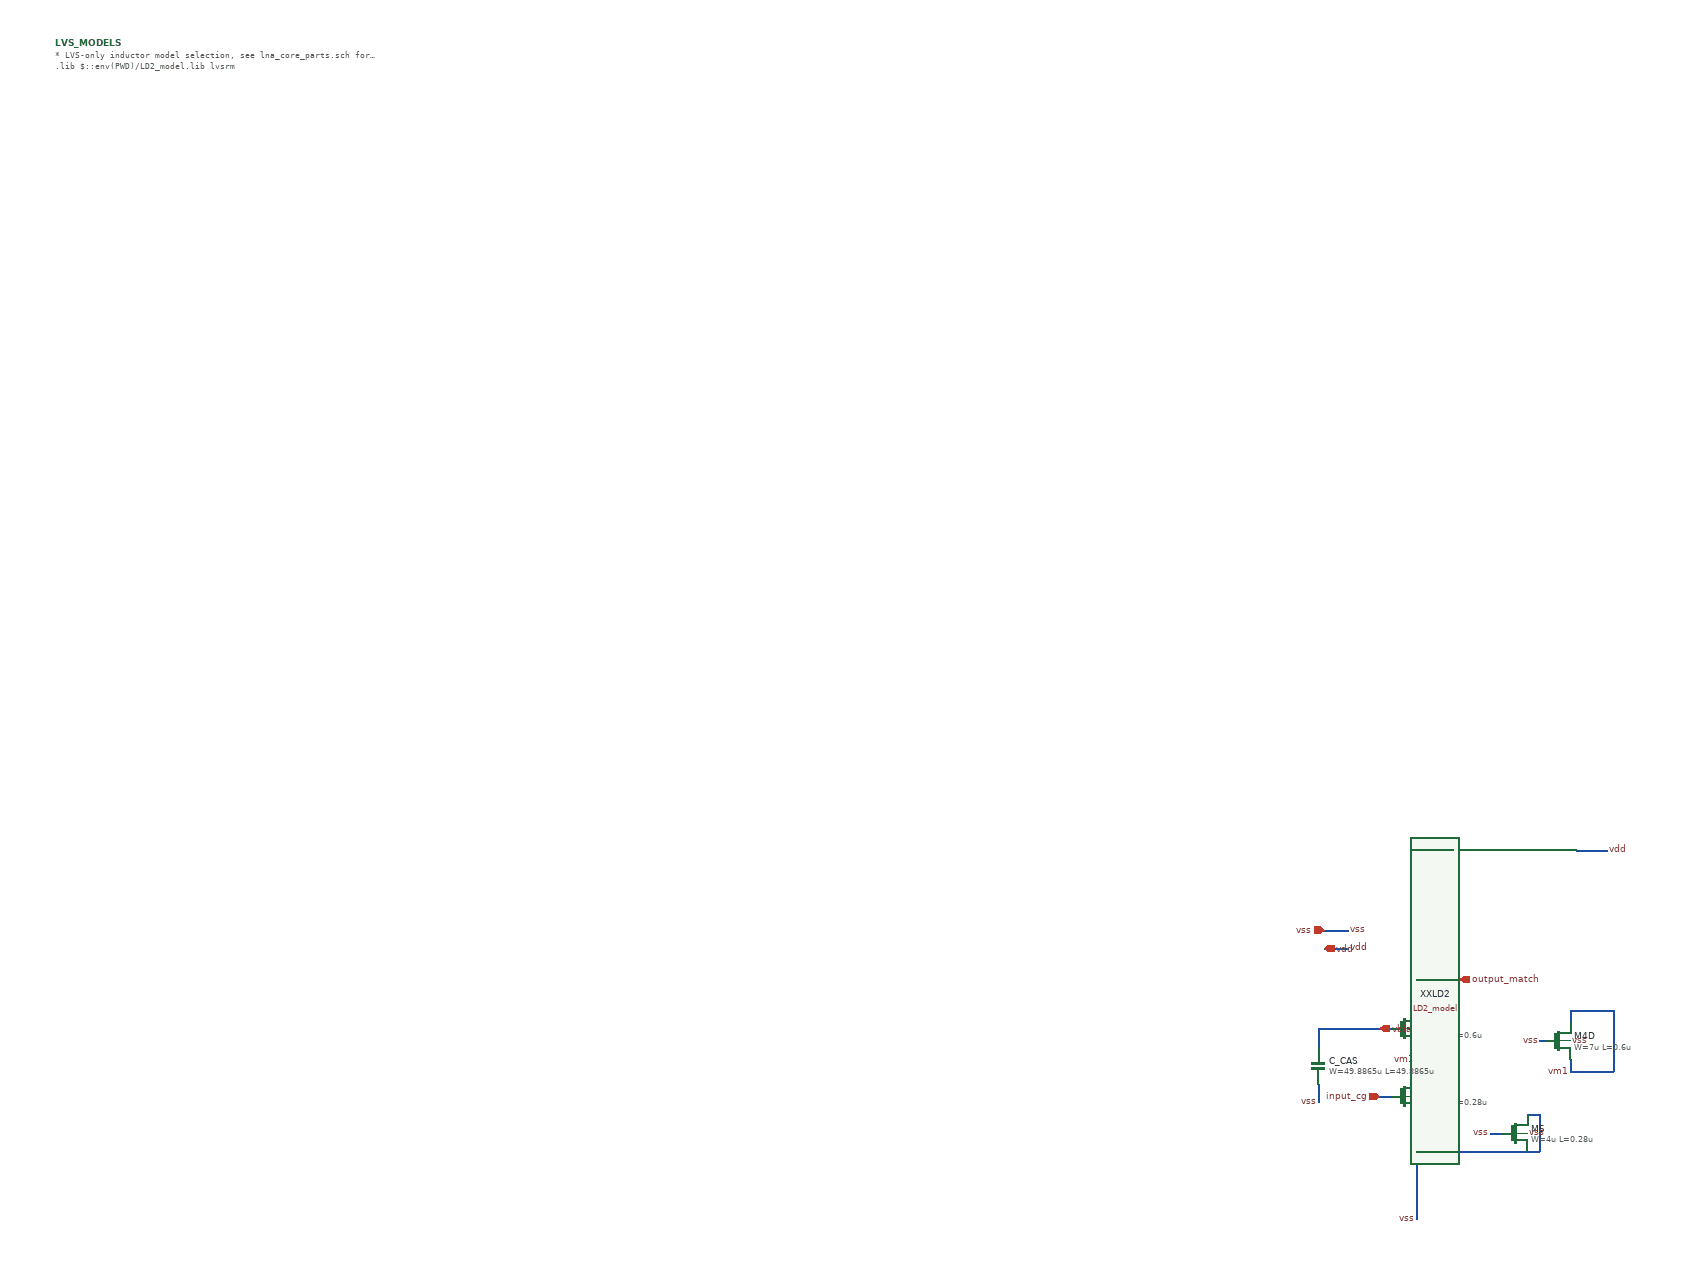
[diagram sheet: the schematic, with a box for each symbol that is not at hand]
v {xschem version=3.4.8RC file_version=1.3}
G {}
K {}
V {}
S {}
F {}
E {}
N 460 -430 460 -410 {lab=vm1}
N 460 -350 460 -330 {lab=vm1}
N 410 -380 420 -380 {lab=vss}
N 210 -290 230 -290 {
lab=vss}
N 210 -260 210 -250 {
lab=vss}
N 150 -290 170 -290 {
lab=input_cg}
N 210 -250 210 -190 {
lab=vss}
N 210 -400 230 -400 {
lab=vss}
N 210 -370 210 -360 {
lab=vm1}
N 150 -400 170 -400 {
lab=vbias_cas}
N 210 -360 210 -320 {
lab=vm1}
N 210 -190 210 -180 {
lab=vss}
N 210 -120 210 -110 {
lab=vss}
N 210 -110 210 -90 {
lab=vss}
N 210 -480 280 -480 {
lab=output_match}
N 210 -490 210 -430 {lab=output_match}
N 210 -200 390 -200 {lab=vss}
N 390 -260 410 -260 {lab=vss}
N 410 -260 410 -200 {lab=vss}
N 390 -200 410 -200 {lab=vss}
N 330 -230 350 -230 {lab=vss}
N 460 -330 530 -330 {lab=vm1}
N 530 -430 530 -330 {lab=vm1}
N 460 -430 530 -430 {lab=vm1}
N 60 -560 100 -560 {lab=vss}
N 210 -690 270 -690 {lab=output_match}
N 60 -530 100 -530 {lab=vdd}
N 210 -690 210 -490 {lab=output_match}
N 470 -690 520 -690 {lab=vdd}
N 50 -400 150 -400 {lab=vbias_cas}
N 50 -400 50 -370 {lab=vbias_cas}
N 50 -310 50 -280 {lab=vss}
N 210 -180 210 -120 {lab=vss}
C {ipin.sym} 150 -290 0 0 {name=p1 lab=input_cg}
C {opin.sym} 280 -480 0 0 {name=p2 lab=output_match}
C {iopin.sym} 60 -530 0 1 {name=p3 lab=vdd}
C {symbols/nfet_05v0.sym} 440 -380 0 0 {name=M4D
L=0.6u
W=7u
nf=2
m=2
ad="'int((nf+1)/2) * W/nf * 0.18u'"
pd="'2*int((nf+1)/2) * (W/nf + 0.18u)'"
as="'int((nf+2)/2) * W/nf * 0.18u'"
ps="'2*int((nf+2)/2) * (W/nf + 0.18u)'"
nrd="'0.18u / W'" nrs="'0.18u / W'"
sa=0 sb=0 sd=0
model=nfet_05v0
spiceprefix=X
}
C {lab_pin.sym} 410 -380 0 0 {name=pM4D_g sig_type=std_logic lab=vss}
C {lab_pin.sym} 460 -380 2 0 {name=pM4D_b sig_type=std_logic lab=vss}
C {symbols/nfet_05v0.sym} 190 -400 0 0 {name=M2
L=0.6u
W=35u
nf=10
m=4
ad="'int((nf+1)/2) * W/nf * 0.18u'"
pd="'2*int((nf+1)/2) * (W/nf + 0.18u)'"
as="'int((nf+2)/2) * W/nf * 0.18u'"
ps="'2*int((nf+2)/2) * (W/nf + 0.18u)'"
nrd="'0.18u / W'" nrs="'0.18u / W'"
sa=0 sb=0 sd=0
model=nfet_05v0
spiceprefix=X
}
C {symbols/nfet_03v3.sym} 190 -290 0 0 {name=M3
L=0.28u
W=20u
nf=10
m=10
ad="'int((nf+1)/2) * W/nf * 0.18u'"
pd="'2*int((nf+1)/2) * (W/nf + 0.18u)'"
as="'int((nf+2)/2) * W/nf * 0.18u'"
ps="'2*int((nf+2)/2) * (W/nf + 0.18u)'"
nrd="'0.18u / W'" nrs="'0.18u / W'"
sa=0 sb=0 sd=0
model=nfet_03v3
spiceprefix=X
}
C {lab_pin.sym} 210 -348.75 0 0 {name=p6 sig_type=std_logic lab=vm1}
C {iopin.sym} 150 -400 0 1 {name=p7 lab=vbias_cas}
C {lab_pin.sym} 210 -90 3 0 {name=p8 sig_type=std_logic lab=vss}
C {lab_pin.sym} 230 -400 2 0 {name=p9 sig_type=std_logic lab=vss}
C {lab_pin.sym} 230 -290 2 0 {name=p10 sig_type=std_logic lab=vss}
C {symbols/nfet_03v3.sym} 370 -230 0 0 {name=M5
L=0.28u
W=4u
nf=2
m=2
ad="'int((nf+1)/2) * W/nf * 0.18u'"
pd="'2*int((nf+1)/2) * (W/nf + 0.18u)'"
as="'int((nf+2)/2) * W/nf * 0.18u'"
ps="'2*int((nf+2)/2) * (W/nf + 0.18u)'"
nrd="'0.18u / W'" nrs="'0.18u / W'"
sa=0 sb=0 sd=0
model=nfet_03v3
spiceprefix=X
}
C {lab_pin.sym} 330 -230 0 0 {name=pM1 sig_type=std_logic lab=vss}
C {lab_pin.sym} 390 -230 2 0 {name=pM2 sig_type=std_logic lab=vss}
C {lab_pin.sym} 460 -330 0 0 {name=p5 sig_type=std_logic lab=vm1}
C {iopin.sym} 60 -560 2 0 {name=p11 lab=vss}
C {lab_pin.sym} 100 -560 2 0 {name=p13 sig_type=std_logic lab=vss
}
C {LD2_model.sym} 370 -690 0 1 {name=XXLD2}
C {lab_pin.sym} 520 -690 0 1 {name=pRLD2_T1 sig_type=std_logic lab=vdd}
C {lab_pin.sym} 100 -530 2 0 {name=p4 sig_type=std_logic lab=vdd
}
C {symbols/cap_mim_2f0fF.sym} 50 -340 2 1 {name=C_CAS
W=49.8865u
L=49.8865u
model=cap_mim_2f0_m4m5_noshield
spiceprefix=X
m=4}
C {lab_pin.sym} 50 -280 3 0 {name=p30 sig_type=std_logic lab=vss}
C {code_shown.sym} -2000 -2000 0 0 {name=LVS_MODELS only_toplevel=true
format="tcleval( @value )"
value="
* LVS-only inductor model selection, see lna_core_parts.sch for details.
.lib $::env(PWD)/LD2_model.lib lvsrm
"}
